One B-rep face of a CAD part: STEP entity #75.
In plain terms, the planar face has unit normal (1, 0, 0).
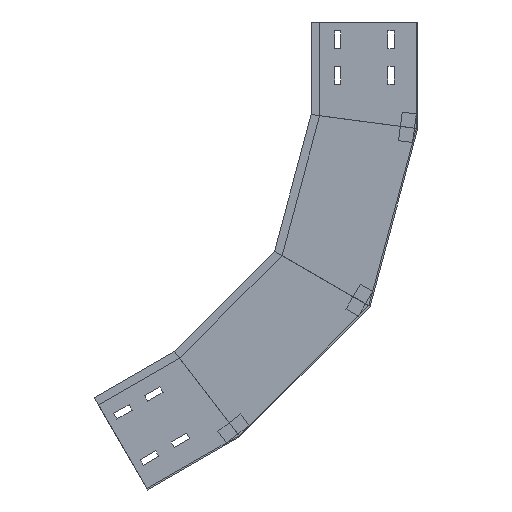
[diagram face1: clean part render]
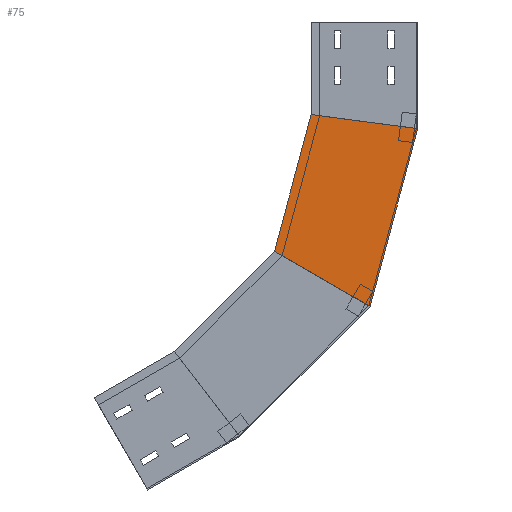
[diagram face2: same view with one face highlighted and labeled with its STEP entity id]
Its self-contained STEP definition (entity closure, numbers rounded to 3 decimals):
#75 = ADVANCED_FACE ( 'NONE', ( #789 ), #462, .F. ) ;
#181 = CARTESIAN_POINT ( 'NONE',  ( 0., 173.1, -294.109 ) ) ;
#193 = ORIENTED_EDGE ( 'NONE', *, *, #803, .T. ) ;
#250 = CARTESIAN_POINT ( 'NONE',  ( 0., 125.087, -366.658 ) ) ;
#349 = LINE ( 'NONE', #1912, #1975 ) ;
#362 = ORIENTED_EDGE ( 'NONE', *, *, #847, .F. ) ;
#462 = PLANE ( 'NONE',  #633 ) ;
#607 = EDGE_LOOP ( 'NONE', ( #362, #2153, #193, #1357 ) ) ;
#633 = AXIS2_PLACEMENT_3D ( 'NONE', #1837, #1855, #1514 ) ;
#718 = VERTEX_POINT ( 'NONE', #972 ) ;
#746 = LINE ( 'NONE', #250, #1748 ) ;
#789 = FACE_OUTER_BOUND ( 'NONE', #607, .T. ) ;
#803 = EDGE_CURVE ( 'NONE', #1123, #913, #1821, .T. ) ;
#824 = DIRECTION ( 'NONE',  ( 0., -0.609, -0.793 ) ) ;
#847 = EDGE_CURVE ( 'NONE', #718, #943, #2064, .T. ) ;
#871 = DIRECTION ( 'NONE',  ( 0., 0.707, -0.707 ) ) ;
#913 = VERTEX_POINT ( 'NONE', #1503 ) ;
#943 = VERTEX_POINT ( 'NONE', #1384 ) ;
#972 = CARTESIAN_POINT ( 'NONE',  ( 0., 201.52, -322.529 ) ) ;
#1014 = EDGE_CURVE ( 'NONE', #718, #1123, #746, .T. ) ;
#1123 = VERTEX_POINT ( 'NONE', #1666 ) ;
#1263 = DIRECTION ( 'NONE',  ( 0., -0.866, -0.5 ) ) ;
#1296 = CARTESIAN_POINT ( 'NONE',  ( 0., 67.034, -400.175 ) ) ;
#1357 = ORIENTED_EDGE ( 'NONE', *, *, #1396, .F. ) ;
#1384 = CARTESIAN_POINT ( 'NONE',  ( 0., 342.277, -463.286 ) ) ;
#1396 = EDGE_CURVE ( 'NONE', #943, #913, #349, .T. ) ;
#1503 = CARTESIAN_POINT ( 'NONE',  ( 0., 250.175, -583.315 ) ) ;
#1514 = DIRECTION ( 'NONE',  ( 0., 0., 1. ) ) ;
#1645 = VECTOR ( 'NONE', #871, 1000. ) ;
#1666 = CARTESIAN_POINT ( 'NONE',  ( 0., 67.034, -400.175 ) ) ;
#1748 = VECTOR ( 'NONE', #1263, 1000. ) ;
#1821 = LINE ( 'NONE', #1296, #1969 ) ;
#1837 = CARTESIAN_POINT ( 'NONE',  ( 0., 67.034, -400.175 ) ) ;
#1855 = DIRECTION ( 'NONE',  ( -1., 0., 0. ) ) ;
#1912 = CARTESIAN_POINT ( 'NONE',  ( 0., 270.755, -556.495 ) ) ;
#1969 = VECTOR ( 'NONE', #1996, 1000. ) ;
#1975 = VECTOR ( 'NONE', #824, 1000. ) ;
#1996 = DIRECTION ( 'NONE',  ( 0., 0.707, -0.707 ) ) ;
#2064 = LINE ( 'NONE', #181, #1645 ) ;
#2153 = ORIENTED_EDGE ( 'NONE', *, *, #1014, .T. ) ;
